VERSION 5.7 ;
  NOWIREEXTENSIONATPIN ON ;
  DIVIDERCHAR "/" ;
  BUSBITCHARS "[]" ;
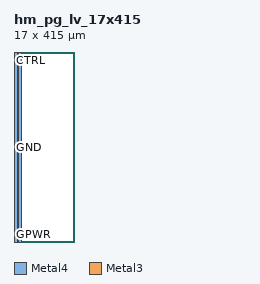
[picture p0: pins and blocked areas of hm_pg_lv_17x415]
MACRO hm_pg_lv_17x415
  CLASS BLOCK ;
  FOREIGN hm_pg_lv_17x415 ;
  ORIGIN 0.000 0.000 ;
  SIZE 17.000 BY 415.000 ;
  PIN VPWR
    DIRECTION INOUT ;
    USE POWER ;
    PORT
      LAYER Metal4 ;
        RECT 0.000 0.000 7.000 415.000 ;
    END
  END VPWR
  PIN GND
    DIRECTION INOUT ;
    USE GROUND ;
    PORT
      LAYER Metal4 ;
        RECT 7.300 0.000 9.700 415.000 ;
    END
  END GND
  PIN GPWR
    DIRECTION INOUT ;
    USE POWER ;
    PORT
      LAYER Metal4 ;
        RECT 10.000 0.000 17.000 415.000 ;
    END
  END GPWR
  PIN CTRL
    DIRECTION INPUT ;
    USE SIGNAL ;
    ANTENNAGATEAREA 1.560000 ;
    PORT
      LAYER Metal3 ;
        RECT 8.235 414.500 10.635 415.000 ;
    END
  END CTRL
  OBS
      LAYER GatPoly ;
        RECT 0.030 0.240 16.760 414.360 ;
      LAYER Metal1 ;
        RECT 0.030 0.240 16.760 414.360 ;
      LAYER Metal2 ;
        RECT 0.000 1.170 16.220 415.000 ;
      LAYER Metal3 ;
        RECT 0.000 0.000 17.000 414.190 ;
  END
END hm_pg_lv_17x415
END LIBRARY

